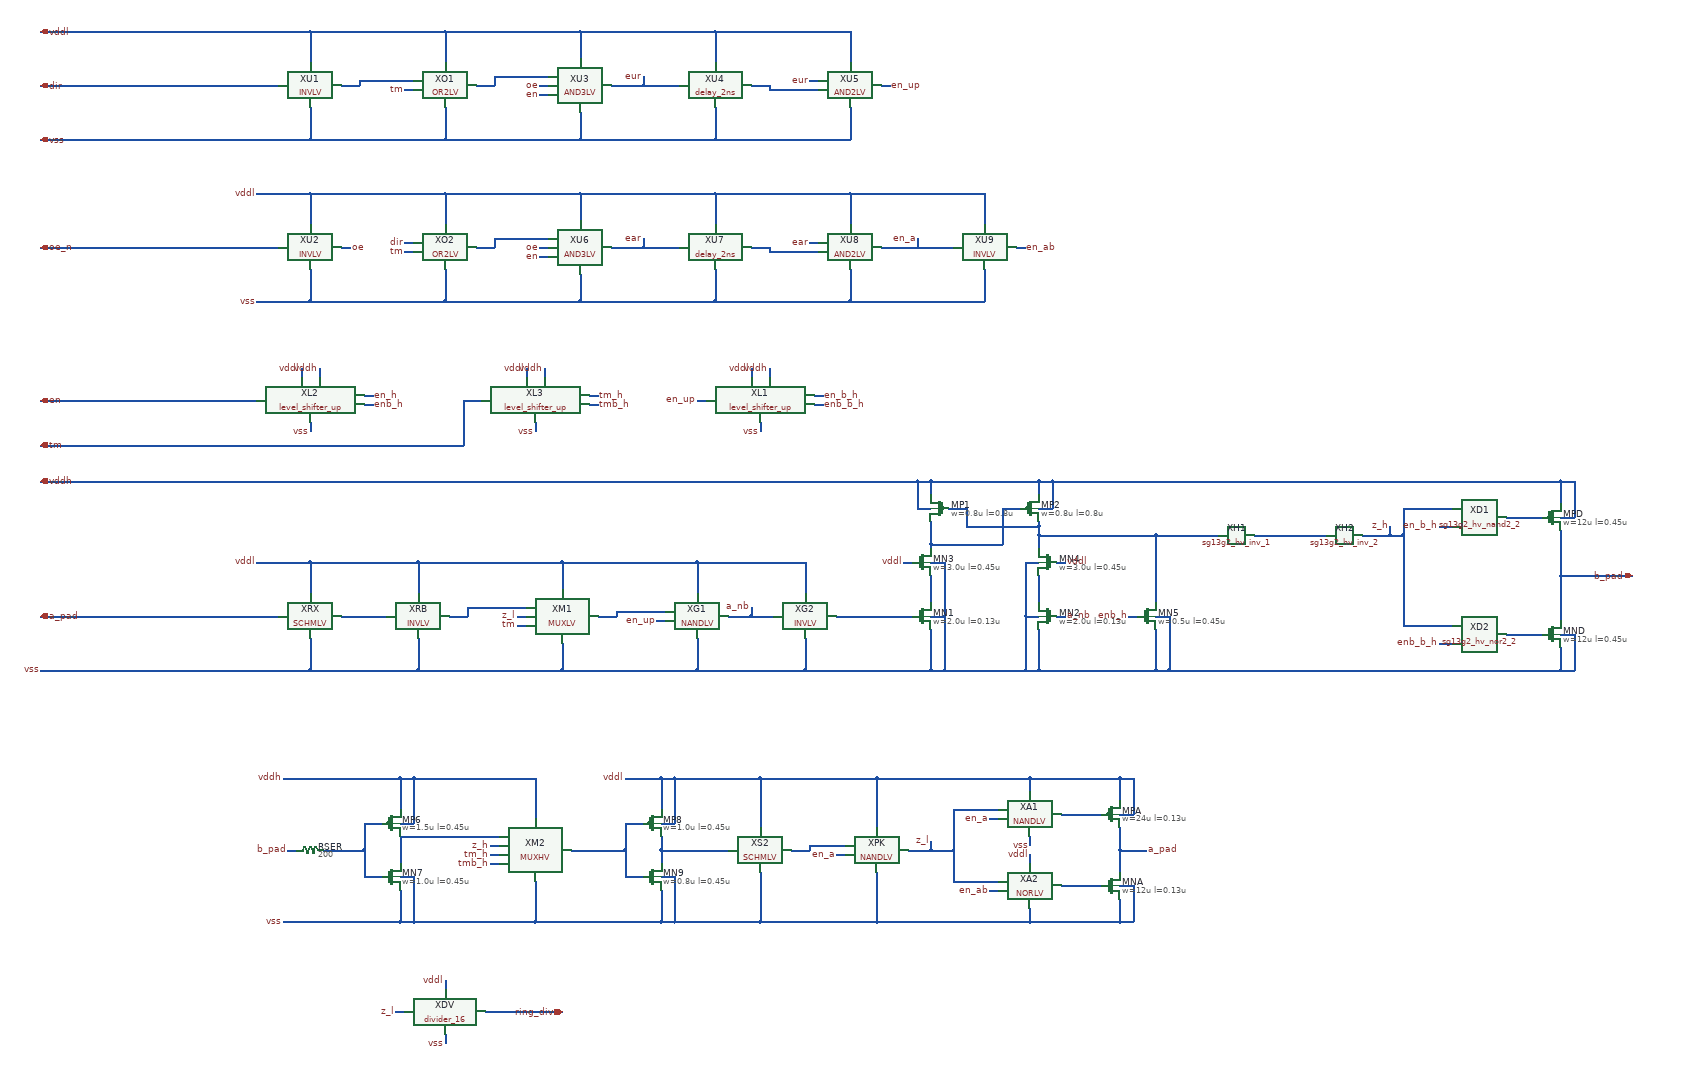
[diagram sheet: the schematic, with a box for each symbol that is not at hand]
v {xschem version=3.4.4 file_version=1.2}
G {}
K {}
V {}
S {}
E {}
N -600 0 -70 0 {}
N 70 0 110 0 {}
N 110 -10 110 0 {}
N 110 -10 230 -10 {}
N 210 10 230 10 {}
N 370 0 410 0 {}
N 410 -20 410 0 {}
N 410 -20 530 -20 {}
N 510 0 530 0 {}
N 510 20 530 20 {}
N 670 0 740 0 {}
N 740 0 820 0 {}
N 740 -20 740 0 {}
N 980 0 1020 0 {}
N 1020 0 1020 10 {}
N 1020 10 1130 10 {}
N 1110 -10 1130 -10 {}
N 1270 0 1290 0 {}
N 0 -120 0 -50 {}
N 0 50 0 120 {}
N 300 -120 300 -50 {}
N 300 50 300 120 {}
N 600 -120 600 -60 {}
N 600 60 600 120 {}
N 900 -120 900 -50 {}
N 900 50 900 120 {}
N 1200 -120 1200 -50 {}
N 1200 50 1200 120 {}
N -600 -120 0 -120 {}
N 0 -120 300 -120 {}
N 300 -120 600 -120 {}
N 600 -120 900 -120 {}
N 900 -120 1200 -120 {}
N -600 120 0 120 {}
N 0 120 300 120 {}
N 300 120 600 120 {}
N 600 120 900 120 {}
N 900 120 1200 120 {}
N -600 360 -70 360 {}
N 70 360 90 360 {}
N 210 350 230 350 {}
N 210 370 230 370 {}
N 370 360 410 360 {}
N 410 340 410 360 {}
N 410 340 530 340 {}
N 510 360 530 360 {}
N 510 380 530 380 {}
N 670 360 740 360 {}
N 740 360 820 360 {}
N 740 340 740 360 {}
N 980 360 1020 360 {}
N 1020 360 1020 370 {}
N 1020 370 1130 370 {}
N 1110 350 1130 350 {}
N 1270 360 1350 360 {}
N 1350 360 1430 360 {}
N 1350 340 1350 360 {}
N 1570 360 1590 360 {}
N 0 240 0 310 {}
N 0 410 0 480 {}
N 300 240 300 310 {}
N 300 410 300 480 {}
N 600 240 600 300 {}
N 600 420 600 480 {}
N 900 240 900 310 {}
N 900 410 900 480 {}
N 1200 240 1200 310 {}
N 1200 410 1200 480 {}
N 1500 240 1500 310 {}
N 1500 410 1500 480 {}
N -120 240 0 240 {}
N 0 240 300 240 {}
N 300 240 600 240 {}
N 600 240 900 240 {}
N 900 240 1200 240 {}
N 1200 240 1500 240 {}
N -120 480 0 480 {}
N 0 480 300 480 {}
N 300 480 600 480 {}
N 600 480 900 480 {}
N 900 480 1200 480 {}
N 1200 480 1500 480 {}
N -20 630 -20 650 {}
N 20 630 20 650 {}
N 0 750 0 770 {}
N 480 630 480 650 {}
N 520 630 520 650 {}
N 500 750 500 770 {}
N 980 630 980 650 {}
N 1020 630 1020 650 {}
N 1000 750 1000 770 {}
N -600 700 -120 700 {}
N -600 800 340 800 {}
N 340 700 340 800 {}
N 340 700 380 700 {}
N 860 700 880 700 {}
N 120 690 140 690 {}
N 120 710 140 710 {}
N 620 690 640 690 {}
N 620 710 640 710 {}
N 1120 690 1140 690 {}
N 1120 710 1140 710 {}
N -600 1180 -70 1180 {}
N 70 1180 170 1180 {}
N 310 1180 350 1180 {}
N 350 1160 350 1180 {}
N 350 1160 480 1160 {}
N 460 1180 480 1180 {}
N 460 1200 480 1200 {}
N 640 1180 680 1180 {}
N 680 1170 680 1180 {}
N 680 1170 790 1170 {}
N 770 1190 790 1190 {}
N 930 1180 980 1180 {}
N 980 1180 1030 1180 {}
N 980 1160 980 1180 {}
N 0 1060 0 1130 {}
N 0 1230 0 1300 {}
N 240 1060 240 1130 {}
N 240 1230 240 1300 {}
N 560 1060 560 1120 {}
N 560 1240 560 1300 {}
N 860 1060 860 1130 {}
N 860 1230 860 1300 {}
N 1100 1060 1100 1130 {}
N 1100 1230 1100 1300 {}
N -120 1060 0 1060 {}
N 0 1060 240 1060 {}
N 240 1060 560 1060 {}
N 560 1060 860 1060 {}
N 860 1060 1100 1060 {}
N 1170 1180 1340 1180 {}
N 1380 880 1380 910 {}
N 1620 880 1620 910 {}
N 1350 940 1380 940 {}
N 1350 880 1350 940 {}
N 1620 940 1650 940 {}
N 1650 880 1650 940 {}
N 1380 970 1380 1020 {}
N 1380 1020 1380 1030 {}
N 1380 1090 1380 1150 {}
N 1380 1210 1380 1300 {}
N 1620 970 1620 980 {}
N 1620 980 1620 1000 {}
N 1620 1000 1620 1030 {}
N 1620 1090 1620 1150 {}
N 1620 1210 1620 1300 {}
N 1380 1060 1410 1060 {}
N 1410 1060 1410 1180 {}
N 1410 1180 1410 1300 {}
N 1380 1180 1410 1180 {}
N 1590 1060 1620 1060 {}
N 1590 1060 1590 1180 {}
N 1590 1180 1590 1300 {}
N 1590 1180 1620 1180 {}
N 1380 1020 1540 1020 {}
N 1540 940 1540 1020 {}
N 1540 940 1580 940 {}
N 1460 980 1620 980 {}
N 1460 940 1460 980 {}
N 1420 940 1460 940 {}
N 1320 1060 1340 1060 {}
N 1660 1060 1680 1060 {}
N 1660 1180 1680 1180 {}
N 1880 1000 1880 1150 {}
N 1880 1210 1880 1300 {}
N 1880 1180 1910 1180 {}
N 1910 1180 1910 1300 {}
N 1820 1180 1840 1180 {}
N 1620 1000 1880 1000 {}
N 1880 1000 2020 1000 {}
N 2100 1000 2260 1000 {}
N 2340 1000 2400 1000 {}
N 2400 1000 2430 1000 {}
N 2400 980 2400 1000 {}
N 2430 940 2540 940 {}
N 2430 940 2430 1000 {}
N 2430 1000 2430 1200 {}
N 2430 1200 2540 1200 {}
N 2510 980 2540 980 {}
N 2510 1240 2540 1240 {}
N 2660 960 2740 960 {}
N 2660 1220 2740 1220 {}
N 2780 880 2780 930 {}
N 2780 960 2810 960 {}
N 2810 880 2810 960 {}
N 2780 1250 2780 1300 {}
N 2780 1220 2810 1220 {}
N 2810 1220 2810 1300 {}
N 2780 990 2780 1090 {}
N 2780 1090 2780 1190 {}
N 2780 1090 2940 1090 {}
N -600 880 1350 880 {}
N 1350 880 1380 880 {}
N 1380 880 1620 880 {}
N 1620 880 1650 880 {}
N 1650 880 2060 880 {}
N 2060 880 2300 880 {}
N 2300 880 2600 880 {}
N 2600 880 2780 880 {}
N 2780 880 2810 880 {}
N -600 1300 0 1300 {}
N 0 1300 240 1300 {}
N 240 1300 560 1300 {}
N 560 1300 860 1300 {}
N 860 1300 1100 1300 {}
N 1100 1300 1380 1300 {}
N 1380 1300 1410 1300 {}
N 1410 1300 1590 1300 {}
N 1590 1300 1620 1300 {}
N 1620 1300 1880 1300 {}
N 1880 1300 1910 1300 {}
N 1910 1300 2060 1300 {}
N 2060 1300 2300 1300 {}
N 2300 1300 2600 1300 {}
N 2600 1300 2780 1300 {}
N 2780 1300 2810 1300 {}
N -50 1700 -30 1700 {}
N 30 1700 120 1700 {}
N 120 1640 160 1640 {}
N 120 1640 120 1700 {}
N 120 1700 120 1760 {}
N 120 1760 160 1760 {}
N 200 1670 200 1730 {}
N 200 1540 200 1610 {}
N 200 1640 230 1640 {}
N 230 1540 230 1640 {}
N 200 1790 200 1860 {}
N 200 1760 230 1760 {}
N 230 1760 230 1860 {}
N 200 1670 420 1670 {}
N 400 1690 420 1690 {}
N 400 1710 420 1710 {}
N 400 1730 420 1730 {}
N 500 1540 500 1630 {}
N 500 1770 500 1860 {}
N -60 1540 200 1540 {}
N 200 1540 230 1540 {}
N 230 1540 500 1540 {}
N -60 1860 200 1860 {}
N 200 1860 230 1860 {}
N 230 1860 500 1860 {}
N 580 1700 700 1700 {}
N 700 1640 740 1640 {}
N 700 1640 700 1700 {}
N 700 1700 700 1760 {}
N 700 1760 740 1760 {}
N 780 1670 780 1700 {}
N 780 1700 780 1730 {}
N 780 1540 780 1610 {}
N 780 1640 810 1640 {}
N 810 1540 810 1640 {}
N 780 1790 780 1860 {}
N 780 1760 810 1760 {}
N 810 1760 810 1860 {}
N 780 1700 930 1700 {}
N 1070 1700 1110 1700 {}
N 1110 1690 1110 1700 {}
N 1110 1690 1190 1690 {}
N 1170 1710 1190 1710 {}
N 1330 1700 1380 1700 {}
N 1380 1700 1430 1700 {}
N 1380 1680 1380 1700 {}
N 1430 1610 1530 1610 {}
N 1430 1610 1430 1700 {}
N 1430 1700 1430 1770 {}
N 1430 1770 1530 1770 {}
N 1510 1630 1530 1630 {}
N 1510 1790 1530 1790 {}
N 1600 1670 1600 1690 {}
N 1600 1710 1600 1730 {}
N 1670 1620 1760 1620 {}
N 1670 1780 1760 1780 {}
N 1800 1540 1800 1590 {}
N 1800 1620 1830 1620 {}
N 1830 1540 1830 1620 {}
N 1800 1810 1800 1860 {}
N 1800 1780 1830 1780 {}
N 1830 1780 1830 1860 {}
N 1800 1650 1800 1700 {}
N 1800 1700 1800 1750 {}
N 1800 1700 1860 1700 {}
N 1000 1540 1000 1650 {}
N 1000 1750 1000 1860 {}
N 1260 1540 1260 1650 {}
N 1260 1750 1260 1860 {}
N 700 1540 780 1540 {}
N 780 1540 810 1540 {}
N 810 1540 1000 1540 {}
N 1000 1540 1260 1540 {}
N 1260 1540 1600 1540 {}
N 1600 1540 1800 1540 {}
N 1800 1540 1830 1540 {}
N 1600 1540 1600 1570 {}
N 1600 1830 1600 1860 {}
N 500 1860 780 1860 {}
N 780 1860 810 1860 {}
N 810 1860 1000 1860 {}
N 1000 1860 1260 1860 {}
N 1260 1860 1600 1860 {}
N 1600 1860 1800 1860 {}
N 1800 1860 1830 1860 {}
N 190 2060 210 2060 {}
N 390 2060 560 2060 {}
N 300 1990 300 2010 {}
N 300 2110 300 2130 {}
C {logic_gates/INVLV.sym} 0 0 0 0 {name=XU1}
C {logic_gates/OR2LV.sym} 300 0 0 0 {name=XO1}
C {logic_gates/AND3LV.sym} 600 0 0 0 {name=XU3}
C {schematics/delay_2ns.sym} 900 0 0 0 {name=XU4}
C {logic_gates/AND2LV.sym} 1200 0 0 0 {name=XU5}
C {devices/iopin.sym} -600 0 0 1 {name=p0 lab=dir}
C {devices/lab_pin.sym} 210 10 0 0 {name=l0 sig_type=std_logic lab=tm}
C {devices/lab_pin.sym} 510 0 0 0 {name=l1 sig_type=std_logic lab=oe}
C {devices/lab_pin.sym} 510 20 0 0 {name=l2 sig_type=std_logic lab=en}
C {devices/lab_pin.sym} 740 -20 0 0 {name=l3 sig_type=std_logic lab=eur}
C {devices/lab_pin.sym} 1110 -10 0 0 {name=l4 sig_type=std_logic lab=eur}
C {devices/lab_pin.sym} 1290 0 0 1 {name=l5 sig_type=std_logic lab=en_up}
C {devices/iopin.sym} -600 -120 0 1 {name=p1 lab=vddl}
C {devices/iopin.sym} -600 120 0 1 {name=p2 lab=vss}
C {logic_gates/INVLV.sym} 0 360 0 0 {name=XU2}
C {logic_gates/OR2LV.sym} 300 360 0 0 {name=XO2}
C {logic_gates/AND3LV.sym} 600 360 0 0 {name=XU6}
C {schematics/delay_2ns.sym} 900 360 0 0 {name=XU7}
C {logic_gates/AND2LV.sym} 1200 360 0 0 {name=XU8}
C {logic_gates/INVLV.sym} 1500 360 0 0 {name=XU9}
C {devices/iopin.sym} -600 360 0 1 {name=p3 lab=oe_n}
C {devices/lab_pin.sym} 90 360 0 1 {name=l6 sig_type=std_logic lab=oe}
C {devices/lab_pin.sym} 210 350 0 0 {name=l7 sig_type=std_logic lab=dir}
C {devices/lab_pin.sym} 210 370 0 0 {name=l8 sig_type=std_logic lab=tm}
C {devices/lab_pin.sym} 510 360 0 0 {name=l9 sig_type=std_logic lab=oe}
C {devices/lab_pin.sym} 510 380 0 0 {name=l10 sig_type=std_logic lab=en}
C {devices/lab_pin.sym} 740 340 0 0 {name=l11 sig_type=std_logic lab=ear}
C {devices/lab_pin.sym} 1110 350 0 0 {name=l12 sig_type=std_logic lab=ear}
C {devices/lab_pin.sym} 1350 340 0 0 {name=l13 sig_type=std_logic lab=en_a}
C {devices/lab_pin.sym} 1590 360 0 1 {name=l14 sig_type=std_logic lab=en_ab}
C {devices/lab_pin.sym} -120 240 0 0 {name=l15 sig_type=std_logic lab=vddl}
C {devices/lab_pin.sym} -120 480 0 0 {name=l16 sig_type=std_logic lab=vss}
C {schematics/level_shifter_up.sym} 0 700 0 0 {name=XL2}
C {devices/lab_pin.sym} -20 630 1 0 {name=l17 sig_type=std_logic lab=vddl}
C {devices/lab_pin.sym} 20 630 1 0 {name=l18 sig_type=std_logic lab=vddh}
C {devices/lab_pin.sym} 0 770 0 0 {name=l19 sig_type=std_logic lab=vss}
C {schematics/level_shifter_up.sym} 500 700 0 0 {name=XL3}
C {devices/lab_pin.sym} 480 630 1 0 {name=l20 sig_type=std_logic lab=vddl}
C {devices/lab_pin.sym} 520 630 1 0 {name=l21 sig_type=std_logic lab=vddh}
C {devices/lab_pin.sym} 500 770 0 0 {name=l22 sig_type=std_logic lab=vss}
C {schematics/level_shifter_up.sym} 1000 700 0 0 {name=XL1}
C {devices/lab_pin.sym} 980 630 1 0 {name=l23 sig_type=std_logic lab=vddl}
C {devices/lab_pin.sym} 1020 630 1 0 {name=l24 sig_type=std_logic lab=vddh}
C {devices/lab_pin.sym} 1000 770 0 0 {name=l25 sig_type=std_logic lab=vss}
C {devices/iopin.sym} -600 700 0 1 {name=p4 lab=en}
C {devices/iopin.sym} -600 800 0 1 {name=p5 lab=tm}
C {devices/lab_pin.sym} 860 700 0 0 {name=l26 sig_type=std_logic lab=en_up}
C {devices/lab_pin.sym} 140 690 0 1 {name=l27 sig_type=std_logic lab=en_h}
C {devices/lab_pin.sym} 140 710 0 1 {name=l28 sig_type=std_logic lab=enb_h}
C {devices/lab_pin.sym} 640 690 0 1 {name=l29 sig_type=std_logic lab=tm_h}
C {devices/lab_pin.sym} 640 710 0 1 {name=l30 sig_type=std_logic lab=tmb_h}
C {devices/lab_pin.sym} 1140 690 0 1 {name=l31 sig_type=std_logic lab=en_b_h}
C {devices/lab_pin.sym} 1140 710 0 1 {name=l32 sig_type=std_logic lab=enb_b_h}
C {logic_gates/SCHMLV.sym} 0 1180 0 0 {name=XRX}
C {logic_gates/INVLV.sym} 240 1180 0 0 {name=XRB}
C {logic_gates/MUXLV.sym} 560 1180 0 0 {name=XM1}
C {logic_gates/NANDLV.sym} 860 1180 0 0 {name=XG1}
C {logic_gates/INVLV.sym} 1100 1180 0 0 {name=XG2}
C {devices/iopin.sym} -600 1180 0 1 {name=p6 lab=a_pad}
C {devices/lab_pin.sym} 460 1180 0 0 {name=l33 sig_type=std_logic lab=z_l}
C {devices/lab_pin.sym} 460 1200 0 0 {name=l34 sig_type=std_logic lab=tm}
C {devices/lab_pin.sym} 770 1190 0 0 {name=l35 sig_type=std_logic lab=en_up}
C {devices/lab_pin.sym} 980 1160 0 0 {name=l36 sig_type=std_logic lab=a_nb}
C {devices/lab_pin.sym} -120 1060 0 0 {name=l37 sig_type=std_logic lab=vddl}
C {sg13cmos5l_pr/sg13_hv_pmos.sym} 1400 940 0 1 {name=MP1 model=sg13_hv_pmos w=0.8u l=0.8u ng=1 m=1 spiceprefix=X}
C {sg13cmos5l_pr/sg13_hv_pmos.sym} 1600 940 0 0 {name=MP2 model=sg13_hv_pmos w=0.8u l=0.8u ng=1 m=1 spiceprefix=X}
C {sg13cmos5l_pr/sg13_hv_nmos.sym} 1360 1060 0 0 {name=MN3 model=sg13_hv_nmos w=3.0u l=0.45u ng=1 m=1 spiceprefix=X}
C {sg13cmos5l_pr/sg13_hv_nmos.sym} 1640 1060 0 1 {name=MN4 model=sg13_hv_nmos w=3.0u l=0.45u ng=1 m=1 spiceprefix=X}
C {sg13cmos5l_pr/sg13_lv_nmos.sym} 1360 1180 0 0 {name=MN1 model=sg13_lv_nmos w=2.0u l=0.13u ng=1 m=1 spiceprefix=X}
C {sg13cmos5l_pr/sg13_lv_nmos.sym} 1640 1180 0 1 {name=MN2 model=sg13_lv_nmos w=2.0u l=0.13u ng=1 m=1 spiceprefix=X}
C {devices/lab_pin.sym} 1320 1060 0 0 {name=l38 sig_type=std_logic lab=vddl}
C {devices/lab_pin.sym} 1680 1060 0 1 {name=l39 sig_type=std_logic lab=vddl}
C {devices/lab_pin.sym} 1680 1180 0 1 {name=l40 sig_type=std_logic lab=a_nb}
C {sg13cmos5l_pr/sg13_hv_nmos.sym} 1860 1180 0 0 {name=MN5 model=sg13_hv_nmos w=0.5u l=0.45u ng=1 m=1 spiceprefix=X}
C {devices/lab_pin.sym} 1820 1180 0 0 {name=l41 sig_type=std_logic lab=enb_h}
C {sg13g2_hv_inv_1.sym} 2060 1000 0 0 {name=XH1 VDD=vddh VSS=vss prefix=sg13g2_hv_ }
C {sg13g2_hv_inv_2.sym} 2300 1000 0 0 {name=XH2 VDD=vddh VSS=vss prefix=sg13g2_hv_ }
C {sg13g2_hv_nand2_2.sym} 2600 960 0 0 {name=XD1 VDD=vddh VSS=vss prefix=sg13g2_hv_ }
C {sg13g2_hv_nor2_2.sym} 2600 1220 0 0 {name=XD2 VDD=vddh VSS=vss prefix=sg13g2_hv_ }
C {sg13cmos5l_pr/sg13_hv_pmos.sym} 2760 960 0 0 {name=MPD model=sg13_hv_pmos w=12u l=0.45u ng=1 m=8 spiceprefix=X}
C {sg13cmos5l_pr/sg13_hv_nmos.sym} 2760 1220 0 0 {name=MND model=sg13_hv_nmos w=12u l=0.45u ng=1 m=4 spiceprefix=X}
C {devices/lab_pin.sym} 2400 980 0 0 {name=l42 sig_type=std_logic lab=z_h}
C {devices/lab_pin.sym} 2510 980 0 0 {name=l43 sig_type=std_logic lab=en_b_h}
C {devices/lab_pin.sym} 2510 1240 0 0 {name=l44 sig_type=std_logic lab=enb_b_h}
C {devices/iopin.sym} 2940 1090 0 0 {name=p7 lab=b_pad}
C {devices/iopin.sym} -600 880 0 1 {name=p8 lab=vddh}
C {devices/lab_pin.sym} -600 1300 0 0 {name=l47 sig_type=std_logic lab=vss}
C {devices/res.sym} 0 1700 3 0 {name=RSER value=200 footprint=1206 m=1}
C {devices/lab_pin.sym} -50 1700 0 0 {name=l48 sig_type=std_logic lab=b_pad}
C {sg13cmos5l_pr/sg13_hv_pmos.sym} 180 1640 0 0 {name=MP6 model=sg13_hv_pmos w=1.5u l=0.45u ng=1 m=1 spiceprefix=X}
C {sg13cmos5l_pr/sg13_hv_nmos.sym} 180 1760 0 0 {name=MN7 model=sg13_hv_nmos w=1.0u l=0.45u ng=1 m=1 spiceprefix=X}
C {logic_gates/MUXHV.sym} 500 1700 0 0 {name=XM2}
C {devices/lab_pin.sym} 400 1690 0 0 {name=l49 sig_type=std_logic lab=z_h}
C {devices/lab_pin.sym} 400 1710 0 0 {name=l50 sig_type=std_logic lab=tm_h}
C {devices/lab_pin.sym} 400 1730 0 0 {name=l51 sig_type=std_logic lab=tmb_h}
C {devices/lab_pin.sym} -60 1540 0 0 {name=l52 sig_type=std_logic lab=vddh}
C {devices/lab_pin.sym} -60 1860 0 0 {name=l53 sig_type=std_logic lab=vss}
C {sg13cmos5l_pr/sg13_hv_pmos.sym} 760 1640 0 0 {name=MP8 model=sg13_hv_pmos w=1.0u l=0.45u ng=1 m=1 spiceprefix=X}
C {sg13cmos5l_pr/sg13_hv_nmos.sym} 760 1760 0 0 {name=MN9 model=sg13_hv_nmos w=0.8u l=0.45u ng=1 m=1 spiceprefix=X}
C {logic_gates/SCHMLV.sym} 1000 1700 0 0 {name=XS2}
C {logic_gates/NANDLV.sym} 1260 1700 0 0 {name=XPK}
C {devices/lab_pin.sym} 1170 1710 0 0 {name=l54 sig_type=std_logic lab=en_a}
C {logic_gates/NANDLV.sym} 1600 1620 0 0 {name=XA1}
C {logic_gates/NORLV.sym} 1600 1780 0 0 {name=XA2}
C {devices/lab_pin.sym} 1380 1680 0 0 {name=l55 sig_type=std_logic lab=z_l}
C {devices/lab_pin.sym} 1510 1630 0 0 {name=l56 sig_type=std_logic lab=en_a}
C {devices/lab_pin.sym} 1510 1790 0 0 {name=l57 sig_type=std_logic lab=en_ab}
C {devices/lab_pin.sym} 1600 1690 0 0 {name=l58 sig_type=std_logic lab=vss}
C {devices/lab_pin.sym} 1600 1710 0 0 {name=l59 sig_type=std_logic lab=vddl}
C {sg13cmos5l_pr/sg13_lv_pmos.sym} 1780 1620 0 0 {name=MPA model=sg13_lv_pmos w=24u l=0.13u ng=1 m=1 spiceprefix=X}
C {sg13cmos5l_pr/sg13_lv_nmos.sym} 1780 1780 0 0 {name=MNA model=sg13_lv_nmos w=12u l=0.13u ng=1 m=1 spiceprefix=X}
C {devices/lab_pin.sym} 1860 1700 0 1 {name=l60 sig_type=std_logic lab=a_pad}
C {devices/lab_pin.sym} 700 1540 0 0 {name=l61 sig_type=std_logic lab=vddl}
C {schematics/divider_16.sym} 300 2060 0 0 {name=XDV}
C {devices/lab_pin.sym} 190 2060 0 0 {name=l62 sig_type=std_logic lab=z_l}
C {devices/iopin.sym} 560 2060 0 0 {name=p9 lab=ring_div}
C {devices/lab_pin.sym} 300 1990 0 0 {name=l63 sig_type=std_logic lab=vddl}
C {devices/lab_pin.sym} 300 2130 0 0 {name=l64 sig_type=std_logic lab=vss}
